# OpenTallas memory compiler (tools/mem_compiler), ASAP7 abstract view
VERSION 5.7 ;
BUSBITCHARS "[]" ;
DIVIDERCHAR "/" ;
PROPERTYDEFINITIONS
  MACRO width INTEGER ;
  MACRO depth INTEGER ;
  MACRO banks INTEGER ;
END PROPERTYDEFINITIONS
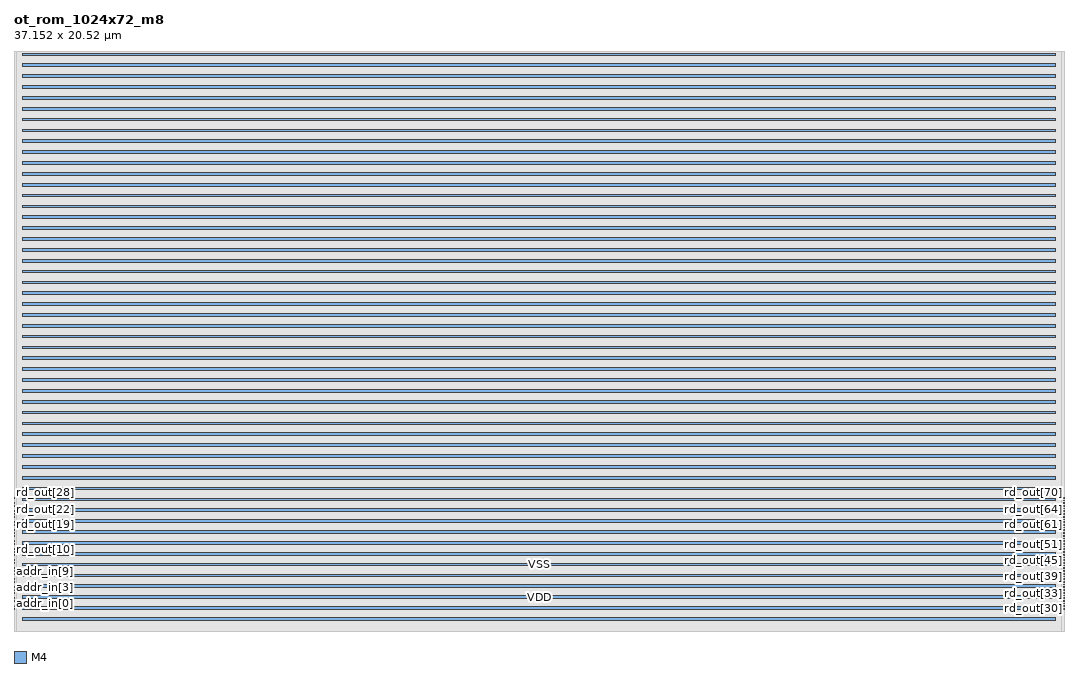
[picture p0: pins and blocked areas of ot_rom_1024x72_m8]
MACRO ot_rom_1024x72_m8
  PROPERTY width 72 ;
  PROPERTY depth 1024 ;
  PROPERTY banks 1 ;
  FOREIGN ot_rom_1024x72_m8 0 0 ;
  SYMMETRY X Y R90 ;
  SIZE 37.152 BY 20.520 ;
  CLASS BLOCK ;
  PIN clk
    DIRECTION INPUT ;
    USE CLOCK ;
    SHAPE ABUTMENT ;
    PORT
      LAYER M4 ;
      RECT 0.000 0.768 0.024 0.792 ;
    END
  END clk
  PIN ce_in
    DIRECTION INPUT ;
    USE SIGNAL ;
    SHAPE ABUTMENT ;
    PORT
      LAYER M4 ;
      RECT 0.000 0.864 0.024 0.888 ;
    END
  END ce_in
  PIN addr_in[0]
    DIRECTION INPUT ;
    USE SIGNAL ;
    SHAPE ABUTMENT ;
    PORT
      LAYER M4 ;
      RECT 0.000 0.960 0.024 0.984 ;
    END
  END addr_in[0]
  PIN addr_in[1]
    DIRECTION INPUT ;
    USE SIGNAL ;
    SHAPE ABUTMENT ;
    PORT
      LAYER M4 ;
      RECT 0.000 1.056 0.024 1.080 ;
    END
  END addr_in[1]
  PIN addr_in[2]
    DIRECTION INPUT ;
    USE SIGNAL ;
    SHAPE ABUTMENT ;
    PORT
      LAYER M4 ;
      RECT 0.000 1.152 0.024 1.176 ;
    END
  END addr_in[2]
  PIN addr_in[3]
    DIRECTION INPUT ;
    USE SIGNAL ;
    SHAPE ABUTMENT ;
    PORT
      LAYER M4 ;
      RECT 0.000 1.248 0.024 1.272 ;
    END
  END addr_in[3]
  PIN addr_in[4]
    DIRECTION INPUT ;
    USE SIGNAL ;
    SHAPE ABUTMENT ;
    PORT
      LAYER M4 ;
      RECT 0.000 1.344 0.024 1.368 ;
    END
  END addr_in[4]
  PIN addr_in[5]
    DIRECTION INPUT ;
    USE SIGNAL ;
    SHAPE ABUTMENT ;
    PORT
      LAYER M4 ;
      RECT 0.000 1.440 0.024 1.464 ;
    END
  END addr_in[5]
  PIN addr_in[6]
    DIRECTION INPUT ;
    USE SIGNAL ;
    SHAPE ABUTMENT ;
    PORT
      LAYER M4 ;
      RECT 0.000 1.536 0.024 1.560 ;
    END
  END addr_in[6]
  PIN addr_in[7]
    DIRECTION INPUT ;
    USE SIGNAL ;
    SHAPE ABUTMENT ;
    PORT
      LAYER M4 ;
      RECT 0.000 1.632 0.024 1.656 ;
    END
  END addr_in[7]
  PIN addr_in[8]
    DIRECTION INPUT ;
    USE SIGNAL ;
    SHAPE ABUTMENT ;
    PORT
      LAYER M4 ;
      RECT 0.000 1.728 0.024 1.752 ;
    END
  END addr_in[8]
  PIN addr_in[9]
    DIRECTION INPUT ;
    USE SIGNAL ;
    SHAPE ABUTMENT ;
    PORT
      LAYER M4 ;
      RECT 0.000 1.824 0.024 1.848 ;
    END
  END addr_in[9]
  PIN rd_out[0]
    DIRECTION OUTPUT ;
    USE SIGNAL ;
    SHAPE ABUTMENT ;
    PORT
      LAYER M4 ;
      RECT 0.000 1.920 0.024 1.944 ;
    END
  END rd_out[0]
  PIN rd_out[1]
    DIRECTION OUTPUT ;
    USE SIGNAL ;
    SHAPE ABUTMENT ;
    PORT
      LAYER M4 ;
      RECT 0.000 2.016 0.024 2.040 ;
    END
  END rd_out[1]
  PIN rd_out[2]
    DIRECTION OUTPUT ;
    USE SIGNAL ;
    SHAPE ABUTMENT ;
    PORT
      LAYER M4 ;
      RECT 0.000 2.112 0.024 2.136 ;
    END
  END rd_out[2]
  PIN rd_out[3]
    DIRECTION OUTPUT ;
    USE SIGNAL ;
    SHAPE ABUTMENT ;
    PORT
      LAYER M4 ;
      RECT 0.000 2.208 0.024 2.232 ;
    END
  END rd_out[3]
  PIN rd_out[4]
    DIRECTION OUTPUT ;
    USE SIGNAL ;
    SHAPE ABUTMENT ;
    PORT
      LAYER M4 ;
      RECT 0.000 2.304 0.024 2.328 ;
    END
  END rd_out[4]
  PIN rd_out[5]
    DIRECTION OUTPUT ;
    USE SIGNAL ;
    SHAPE ABUTMENT ;
    PORT
      LAYER M4 ;
      RECT 0.000 2.400 0.024 2.424 ;
    END
  END rd_out[5]
  PIN rd_out[6]
    DIRECTION OUTPUT ;
    USE SIGNAL ;
    SHAPE ABUTMENT ;
    PORT
      LAYER M4 ;
      RECT 0.000 2.496 0.024 2.520 ;
    END
  END rd_out[6]
  PIN rd_out[7]
    DIRECTION OUTPUT ;
    USE SIGNAL ;
    SHAPE ABUTMENT ;
    PORT
      LAYER M4 ;
      RECT 0.000 2.592 0.024 2.616 ;
    END
  END rd_out[7]
  PIN rd_out[8]
    DIRECTION OUTPUT ;
    USE SIGNAL ;
    SHAPE ABUTMENT ;
    PORT
      LAYER M4 ;
      RECT 0.000 2.688 0.024 2.712 ;
    END
  END rd_out[8]
  PIN rd_out[9]
    DIRECTION OUTPUT ;
    USE SIGNAL ;
    SHAPE ABUTMENT ;
    PORT
      LAYER M4 ;
      RECT 0.000 2.784 0.024 2.808 ;
    END
  END rd_out[9]
  PIN rd_out[10]
    DIRECTION OUTPUT ;
    USE SIGNAL ;
    SHAPE ABUTMENT ;
    PORT
      LAYER M4 ;
      RECT 0.000 2.880 0.024 2.904 ;
    END
  END rd_out[10]
  PIN rd_out[11]
    DIRECTION OUTPUT ;
    USE SIGNAL ;
    SHAPE ABUTMENT ;
    PORT
      LAYER M4 ;
      RECT 0.000 2.976 0.024 3.000 ;
    END
  END rd_out[11]
  PIN rd_out[12]
    DIRECTION OUTPUT ;
    USE SIGNAL ;
    SHAPE ABUTMENT ;
    PORT
      LAYER M4 ;
      RECT 0.000 3.072 0.024 3.096 ;
    END
  END rd_out[12]
  PIN rd_out[13]
    DIRECTION OUTPUT ;
    USE SIGNAL ;
    SHAPE ABUTMENT ;
    PORT
      LAYER M4 ;
      RECT 0.000 3.168 0.024 3.192 ;
    END
  END rd_out[13]
  PIN rd_out[14]
    DIRECTION OUTPUT ;
    USE SIGNAL ;
    SHAPE ABUTMENT ;
    PORT
      LAYER M4 ;
      RECT 0.000 3.264 0.024 3.288 ;
    END
  END rd_out[14]
  PIN rd_out[15]
    DIRECTION OUTPUT ;
    USE SIGNAL ;
    SHAPE ABUTMENT ;
    PORT
      LAYER M4 ;
      RECT 0.000 3.360 0.024 3.384 ;
    END
  END rd_out[15]
  PIN rd_out[16]
    DIRECTION OUTPUT ;
    USE SIGNAL ;
    SHAPE ABUTMENT ;
    PORT
      LAYER M4 ;
      RECT 0.000 3.456 0.024 3.480 ;
    END
  END rd_out[16]
  PIN rd_out[17]
    DIRECTION OUTPUT ;
    USE SIGNAL ;
    SHAPE ABUTMENT ;
    PORT
      LAYER M4 ;
      RECT 0.000 3.552 0.024 3.576 ;
    END
  END rd_out[17]
  PIN rd_out[18]
    DIRECTION OUTPUT ;
    USE SIGNAL ;
    SHAPE ABUTMENT ;
    PORT
      LAYER M4 ;
      RECT 0.000 3.648 0.024 3.672 ;
    END
  END rd_out[18]
  PIN rd_out[19]
    DIRECTION OUTPUT ;
    USE SIGNAL ;
    SHAPE ABUTMENT ;
    PORT
      LAYER M4 ;
      RECT 0.000 3.744 0.024 3.768 ;
    END
  END rd_out[19]
  PIN rd_out[20]
    DIRECTION OUTPUT ;
    USE SIGNAL ;
    SHAPE ABUTMENT ;
    PORT
      LAYER M4 ;
      RECT 0.000 3.840 0.024 3.864 ;
    END
  END rd_out[20]
  PIN rd_out[21]
    DIRECTION OUTPUT ;
    USE SIGNAL ;
    SHAPE ABUTMENT ;
    PORT
      LAYER M4 ;
      RECT 0.000 3.936 0.024 3.960 ;
    END
  END rd_out[21]
  PIN rd_out[22]
    DIRECTION OUTPUT ;
    USE SIGNAL ;
    SHAPE ABUTMENT ;
    PORT
      LAYER M4 ;
      RECT 0.000 4.032 0.024 4.056 ;
    END
  END rd_out[22]
  PIN rd_out[23]
    DIRECTION OUTPUT ;
    USE SIGNAL ;
    SHAPE ABUTMENT ;
    PORT
      LAYER M4 ;
      RECT 0.000 4.128 0.024 4.152 ;
    END
  END rd_out[23]
  PIN rd_out[24]
    DIRECTION OUTPUT ;
    USE SIGNAL ;
    SHAPE ABUTMENT ;
    PORT
      LAYER M4 ;
      RECT 0.000 4.224 0.024 4.248 ;
    END
  END rd_out[24]
  PIN rd_out[25]
    DIRECTION OUTPUT ;
    USE SIGNAL ;
    SHAPE ABUTMENT ;
    PORT
      LAYER M4 ;
      RECT 0.000 4.320 0.024 4.344 ;
    END
  END rd_out[25]
  PIN rd_out[26]
    DIRECTION OUTPUT ;
    USE SIGNAL ;
    SHAPE ABUTMENT ;
    PORT
      LAYER M4 ;
      RECT 0.000 4.416 0.024 4.440 ;
    END
  END rd_out[26]
  PIN rd_out[27]
    DIRECTION OUTPUT ;
    USE SIGNAL ;
    SHAPE ABUTMENT ;
    PORT
      LAYER M4 ;
      RECT 0.000 4.512 0.024 4.536 ;
    END
  END rd_out[27]
  PIN rd_out[28]
    DIRECTION OUTPUT ;
    USE SIGNAL ;
    SHAPE ABUTMENT ;
    PORT
      LAYER M4 ;
      RECT 0.000 4.608 0.024 4.632 ;
    END
  END rd_out[28]
  PIN rd_out[29]
    DIRECTION OUTPUT ;
    USE SIGNAL ;
    SHAPE ABUTMENT ;
    PORT
      LAYER M4 ;
      RECT 0.000 4.704 0.024 4.728 ;
    END
  END rd_out[29]
  PIN rd_out[30]
    DIRECTION OUTPUT ;
    USE SIGNAL ;
    SHAPE ABUTMENT ;
    PORT
      LAYER M4 ;
      RECT 37.128 0.768 37.152 0.792 ;
    END
  END rd_out[30]
  PIN rd_out[31]
    DIRECTION OUTPUT ;
    USE SIGNAL ;
    SHAPE ABUTMENT ;
    PORT
      LAYER M4 ;
      RECT 37.128 0.864 37.152 0.888 ;
    END
  END rd_out[31]
  PIN rd_out[32]
    DIRECTION OUTPUT ;
    USE SIGNAL ;
    SHAPE ABUTMENT ;
    PORT
      LAYER M4 ;
      RECT 37.128 0.960 37.152 0.984 ;
    END
  END rd_out[32]
  PIN rd_out[33]
    DIRECTION OUTPUT ;
    USE SIGNAL ;
    SHAPE ABUTMENT ;
    PORT
      LAYER M4 ;
      RECT 37.128 1.056 37.152 1.080 ;
    END
  END rd_out[33]
  PIN rd_out[34]
    DIRECTION OUTPUT ;
    USE SIGNAL ;
    SHAPE ABUTMENT ;
    PORT
      LAYER M4 ;
      RECT 37.128 1.152 37.152 1.176 ;
    END
  END rd_out[34]
  PIN rd_out[35]
    DIRECTION OUTPUT ;
    USE SIGNAL ;
    SHAPE ABUTMENT ;
    PORT
      LAYER M4 ;
      RECT 37.128 1.248 37.152 1.272 ;
    END
  END rd_out[35]
  PIN rd_out[36]
    DIRECTION OUTPUT ;
    USE SIGNAL ;
    SHAPE ABUTMENT ;
    PORT
      LAYER M4 ;
      RECT 37.128 1.344 37.152 1.368 ;
    END
  END rd_out[36]
  PIN rd_out[37]
    DIRECTION OUTPUT ;
    USE SIGNAL ;
    SHAPE ABUTMENT ;
    PORT
      LAYER M4 ;
      RECT 37.128 1.440 37.152 1.464 ;
    END
  END rd_out[37]
  PIN rd_out[38]
    DIRECTION OUTPUT ;
    USE SIGNAL ;
    SHAPE ABUTMENT ;
    PORT
      LAYER M4 ;
      RECT 37.128 1.536 37.152 1.560 ;
    END
  END rd_out[38]
  PIN rd_out[39]
    DIRECTION OUTPUT ;
    USE SIGNAL ;
    SHAPE ABUTMENT ;
    PORT
      LAYER M4 ;
      RECT 37.128 1.632 37.152 1.656 ;
    END
  END rd_out[39]
  PIN rd_out[40]
    DIRECTION OUTPUT ;
    USE SIGNAL ;
    SHAPE ABUTMENT ;
    PORT
      LAYER M4 ;
      RECT 37.128 1.728 37.152 1.752 ;
    END
  END rd_out[40]
  PIN rd_out[41]
    DIRECTION OUTPUT ;
    USE SIGNAL ;
    SHAPE ABUTMENT ;
    PORT
      LAYER M4 ;
      RECT 37.128 1.824 37.152 1.848 ;
    END
  END rd_out[41]
  PIN rd_out[42]
    DIRECTION OUTPUT ;
    USE SIGNAL ;
    SHAPE ABUTMENT ;
    PORT
      LAYER M4 ;
      RECT 37.128 1.920 37.152 1.944 ;
    END
  END rd_out[42]
  PIN rd_out[43]
    DIRECTION OUTPUT ;
    USE SIGNAL ;
    SHAPE ABUTMENT ;
    PORT
      LAYER M4 ;
      RECT 37.128 2.016 37.152 2.040 ;
    END
  END rd_out[43]
  PIN rd_out[44]
    DIRECTION OUTPUT ;
    USE SIGNAL ;
    SHAPE ABUTMENT ;
    PORT
      LAYER M4 ;
      RECT 37.128 2.112 37.152 2.136 ;
    END
  END rd_out[44]
  PIN rd_out[45]
    DIRECTION OUTPUT ;
    USE SIGNAL ;
    SHAPE ABUTMENT ;
    PORT
      LAYER M4 ;
      RECT 37.128 2.208 37.152 2.232 ;
    END
  END rd_out[45]
  PIN rd_out[46]
    DIRECTION OUTPUT ;
    USE SIGNAL ;
    SHAPE ABUTMENT ;
    PORT
      LAYER M4 ;
      RECT 37.128 2.304 37.152 2.328 ;
    END
  END rd_out[46]
  PIN rd_out[47]
    DIRECTION OUTPUT ;
    USE SIGNAL ;
    SHAPE ABUTMENT ;
    PORT
      LAYER M4 ;
      RECT 37.128 2.400 37.152 2.424 ;
    END
  END rd_out[47]
  PIN rd_out[48]
    DIRECTION OUTPUT ;
    USE SIGNAL ;
    SHAPE ABUTMENT ;
    PORT
      LAYER M4 ;
      RECT 37.128 2.496 37.152 2.520 ;
    END
  END rd_out[48]
  PIN rd_out[49]
    DIRECTION OUTPUT ;
    USE SIGNAL ;
    SHAPE ABUTMENT ;
    PORT
      LAYER M4 ;
      RECT 37.128 2.592 37.152 2.616 ;
    END
  END rd_out[49]
  PIN rd_out[50]
    DIRECTION OUTPUT ;
    USE SIGNAL ;
    SHAPE ABUTMENT ;
    PORT
      LAYER M4 ;
      RECT 37.128 2.688 37.152 2.712 ;
    END
  END rd_out[50]
  PIN rd_out[51]
    DIRECTION OUTPUT ;
    USE SIGNAL ;
    SHAPE ABUTMENT ;
    PORT
      LAYER M4 ;
      RECT 37.128 2.784 37.152 2.808 ;
    END
  END rd_out[51]
  PIN rd_out[52]
    DIRECTION OUTPUT ;
    USE SIGNAL ;
    SHAPE ABUTMENT ;
    PORT
      LAYER M4 ;
      RECT 37.128 2.880 37.152 2.904 ;
    END
  END rd_out[52]
  PIN rd_out[53]
    DIRECTION OUTPUT ;
    USE SIGNAL ;
    SHAPE ABUTMENT ;
    PORT
      LAYER M4 ;
      RECT 37.128 2.976 37.152 3.000 ;
    END
  END rd_out[53]
  PIN rd_out[54]
    DIRECTION OUTPUT ;
    USE SIGNAL ;
    SHAPE ABUTMENT ;
    PORT
      LAYER M4 ;
      RECT 37.128 3.072 37.152 3.096 ;
    END
  END rd_out[54]
  PIN rd_out[55]
    DIRECTION OUTPUT ;
    USE SIGNAL ;
    SHAPE ABUTMENT ;
    PORT
      LAYER M4 ;
      RECT 37.128 3.168 37.152 3.192 ;
    END
  END rd_out[55]
  PIN rd_out[56]
    DIRECTION OUTPUT ;
    USE SIGNAL ;
    SHAPE ABUTMENT ;
    PORT
      LAYER M4 ;
      RECT 37.128 3.264 37.152 3.288 ;
    END
  END rd_out[56]
  PIN rd_out[57]
    DIRECTION OUTPUT ;
    USE SIGNAL ;
    SHAPE ABUTMENT ;
    PORT
      LAYER M4 ;
      RECT 37.128 3.360 37.152 3.384 ;
    END
  END rd_out[57]
  PIN rd_out[58]
    DIRECTION OUTPUT ;
    USE SIGNAL ;
    SHAPE ABUTMENT ;
    PORT
      LAYER M4 ;
      RECT 37.128 3.456 37.152 3.480 ;
    END
  END rd_out[58]
  PIN rd_out[59]
    DIRECTION OUTPUT ;
    USE SIGNAL ;
    SHAPE ABUTMENT ;
    PORT
      LAYER M4 ;
      RECT 37.128 3.552 37.152 3.576 ;
    END
  END rd_out[59]
  PIN rd_out[60]
    DIRECTION OUTPUT ;
    USE SIGNAL ;
    SHAPE ABUTMENT ;
    PORT
      LAYER M4 ;
      RECT 37.128 3.648 37.152 3.672 ;
    END
  END rd_out[60]
  PIN rd_out[61]
    DIRECTION OUTPUT ;
    USE SIGNAL ;
    SHAPE ABUTMENT ;
    PORT
      LAYER M4 ;
      RECT 37.128 3.744 37.152 3.768 ;
    END
  END rd_out[61]
  PIN rd_out[62]
    DIRECTION OUTPUT ;
    USE SIGNAL ;
    SHAPE ABUTMENT ;
    PORT
      LAYER M4 ;
      RECT 37.128 3.840 37.152 3.864 ;
    END
  END rd_out[62]
  PIN rd_out[63]
    DIRECTION OUTPUT ;
    USE SIGNAL ;
    SHAPE ABUTMENT ;
    PORT
      LAYER M4 ;
      RECT 37.128 3.936 37.152 3.960 ;
    END
  END rd_out[63]
  PIN rd_out[64]
    DIRECTION OUTPUT ;
    USE SIGNAL ;
    SHAPE ABUTMENT ;
    PORT
      LAYER M4 ;
      RECT 37.128 4.032 37.152 4.056 ;
    END
  END rd_out[64]
  PIN rd_out[65]
    DIRECTION OUTPUT ;
    USE SIGNAL ;
    SHAPE ABUTMENT ;
    PORT
      LAYER M4 ;
      RECT 37.128 4.128 37.152 4.152 ;
    END
  END rd_out[65]
  PIN rd_out[66]
    DIRECTION OUTPUT ;
    USE SIGNAL ;
    SHAPE ABUTMENT ;
    PORT
      LAYER M4 ;
      RECT 37.128 4.224 37.152 4.248 ;
    END
  END rd_out[66]
  PIN rd_out[67]
    DIRECTION OUTPUT ;
    USE SIGNAL ;
    SHAPE ABUTMENT ;
    PORT
      LAYER M4 ;
      RECT 37.128 4.320 37.152 4.344 ;
    END
  END rd_out[67]
  PIN rd_out[68]
    DIRECTION OUTPUT ;
    USE SIGNAL ;
    SHAPE ABUTMENT ;
    PORT
      LAYER M4 ;
      RECT 37.128 4.416 37.152 4.440 ;
    END
  END rd_out[68]
  PIN rd_out[69]
    DIRECTION OUTPUT ;
    USE SIGNAL ;
    SHAPE ABUTMENT ;
    PORT
      LAYER M4 ;
      RECT 37.128 4.512 37.152 4.536 ;
    END
  END rd_out[69]
  PIN rd_out[70]
    DIRECTION OUTPUT ;
    USE SIGNAL ;
    SHAPE ABUTMENT ;
    PORT
      LAYER M4 ;
      RECT 37.128 4.608 37.152 4.632 ;
    END
  END rd_out[70]
  PIN rd_out[71]
    DIRECTION OUTPUT ;
    USE SIGNAL ;
    SHAPE ABUTMENT ;
    PORT
      LAYER M4 ;
      RECT 37.128 4.704 37.152 4.728 ;
    END
  END rd_out[71]
  PIN VDD
    DIRECTION INOUT ;
    USE POWER ;
    PORT
      LAYER M4 ;
      RECT 0.300 0.384 36.852 0.480 ;
      RECT 0.300 1.152 36.852 1.248 ;
      RECT 0.300 1.920 36.852 2.016 ;
      RECT 0.300 2.688 36.852 2.784 ;
      RECT 0.300 3.456 36.852 3.552 ;
      RECT 0.300 4.224 36.852 4.320 ;
      RECT 0.300 4.992 36.852 5.088 ;
      RECT 0.300 5.760 36.852 5.856 ;
      RECT 0.300 6.528 36.852 6.624 ;
      RECT 0.300 7.296 36.852 7.392 ;
      RECT 0.300 8.064 36.852 8.160 ;
      RECT 0.300 8.832 36.852 8.928 ;
      RECT 0.300 9.600 36.852 9.696 ;
      RECT 0.300 10.368 36.852 10.464 ;
      RECT 0.300 11.136 36.852 11.232 ;
      RECT 0.300 11.904 36.852 12.000 ;
      RECT 0.300 12.672 36.852 12.768 ;
      RECT 0.300 13.440 36.852 13.536 ;
      RECT 0.300 14.208 36.852 14.304 ;
      RECT 0.300 14.976 36.852 15.072 ;
      RECT 0.300 15.744 36.852 15.840 ;
      RECT 0.300 16.512 36.852 16.608 ;
      RECT 0.300 17.280 36.852 17.376 ;
      RECT 0.300 18.048 36.852 18.144 ;
      RECT 0.300 18.816 36.852 18.912 ;
      RECT 0.300 19.584 36.852 19.680 ;
      RECT 0.300 20.352 36.852 20.448 ;
    END
  END VDD
  PIN VSS
    DIRECTION INOUT ;
    USE GROUND ;
    PORT
      LAYER M4 ;
      RECT 0.300 0.768 36.852 0.864 ;
      RECT 0.300 1.536 36.852 1.632 ;
      RECT 0.300 2.304 36.852 2.400 ;
      RECT 0.300 3.072 36.852 3.168 ;
      RECT 0.300 3.840 36.852 3.936 ;
      RECT 0.300 4.608 36.852 4.704 ;
      RECT 0.300 5.376 36.852 5.472 ;
      RECT 0.300 6.144 36.852 6.240 ;
      RECT 0.300 6.912 36.852 7.008 ;
      RECT 0.300 7.680 36.852 7.776 ;
      RECT 0.300 8.448 36.852 8.544 ;
      RECT 0.300 9.216 36.852 9.312 ;
      RECT 0.300 9.984 36.852 10.080 ;
      RECT 0.300 10.752 36.852 10.848 ;
      RECT 0.300 11.520 36.852 11.616 ;
      RECT 0.300 12.288 36.852 12.384 ;
      RECT 0.300 13.056 36.852 13.152 ;
      RECT 0.300 13.824 36.852 13.920 ;
      RECT 0.300 14.592 36.852 14.688 ;
      RECT 0.300 15.360 36.852 15.456 ;
      RECT 0.300 16.128 36.852 16.224 ;
      RECT 0.300 16.896 36.852 16.992 ;
      RECT 0.300 17.664 36.852 17.760 ;
      RECT 0.300 18.432 36.852 18.528 ;
      RECT 0.300 19.200 36.852 19.296 ;
      RECT 0.300 19.968 36.852 20.064 ;
    END
  END VSS
  OBS
    LAYER M1 ;
    RECT 0 0 37.152 20.520 ;
    LAYER M2 ;
    RECT 0 0 37.152 20.520 ;
    LAYER M3 ;
    RECT 0 0 37.152 20.520 ;
    LAYER M4 ;
    RECT 0.072 0 37.080 20.520 ;
  END
END ot_rom_1024x72_m8

END LIBRARY
